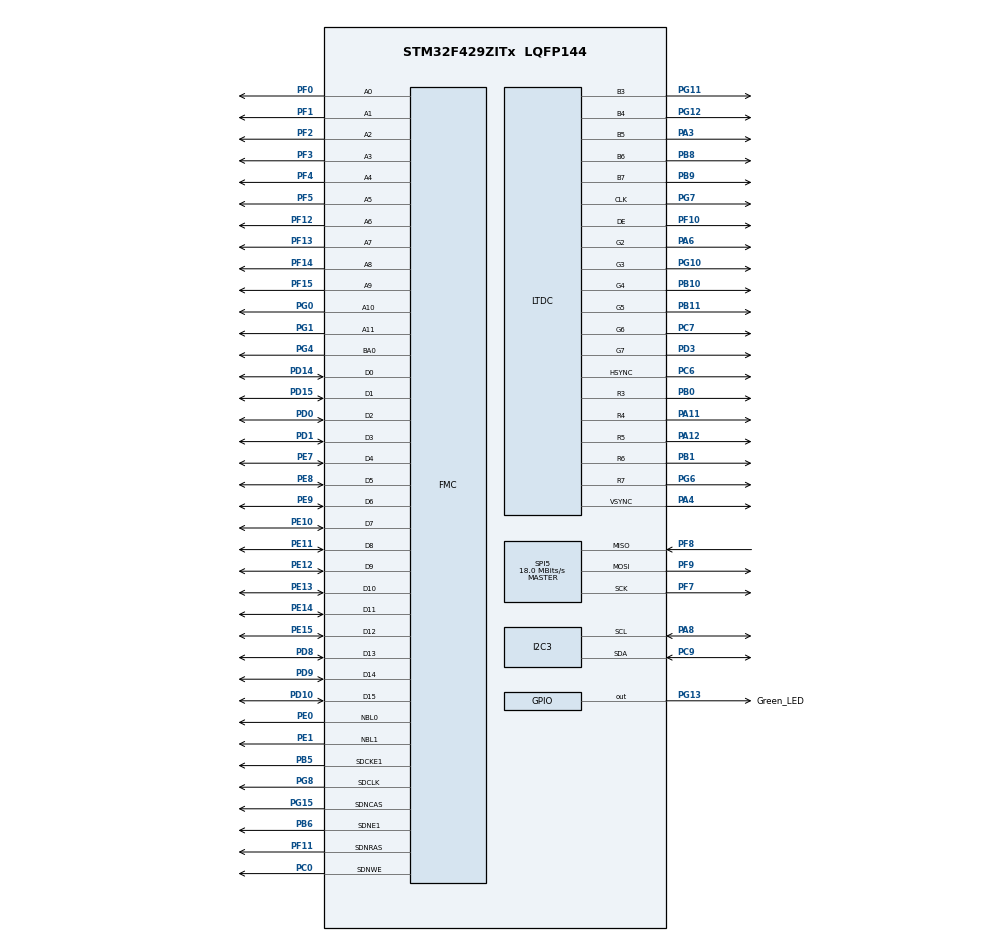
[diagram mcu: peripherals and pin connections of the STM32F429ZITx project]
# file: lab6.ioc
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Mcu.Family=STM32F4
Mcu.Name=STM32F429ZITx
Mcu.Package=LQFP144
NVIC.PriorityGroup=NVIC_PRIORITYGROUP_4
PA11.Mode=RGB565
PA11.Signal=LTDC_R4
PA12.Mode=RGB565
PA12.Signal=LTDC_R5
PA3.Mode=RGB565
PA3.Signal=LTDC_B5
PA4.Mode=RGB565
PA4.Signal=LTDC_VSYNC
PA6.Mode=RGB565
PA6.Signal=LTDC_G2
PA8.GPIO_Pu=GPIO_PULLUP
PA8.GPIO_Speed=GPIO_SPEED_FREQ_LOW
PA8.Mode=I2C
PA8.Signal=I2C3_SCL
PB0.Mode=RGB565
PB0.Signal=LTDC_R3
PB1.Mode=RGB565
PB1.Signal=LTDC_R6
PB10.Mode=RGB565
PB10.Signal=LTDC_G4
PB11.Mode=RGB565
PB11.Signal=LTDC_G5
PB5.Mode=SdramChipSelect2_2
PB5.Signal=FMC_SDCKE1
PB6.Mode=SdramChipSelect2_2
PB6.Signal=FMC_SDNE1
PB8.Mode=RGB565
PB8.Signal=LTDC_B6
PB9.Mode=RGB565
PB9.Signal=LTDC_B7
PC0.Signal=FMC_SDNWE
PC6.Mode=RGB565
PC6.Signal=LTDC_HSYNC
PC7.Mode=RGB565
PC7.Signal=LTDC_G6
PC9.GPIO_Pu=GPIO_PULLUP
PC9.GPIO_Speed=GPIO_SPEED_FREQ_LOW
PC9.Mode=I2C
PC9.Signal=I2C3_SDA
PD0.Signal=FMC_D2_DA2
PD1.Signal=FMC_D3_DA3
PD10.Signal=FMC_D15_DA15
PD14.Signal=FMC_D0_DA0
PD15.Signal=FMC_D1_DA1
PD3.Mode=RGB565
PD3.Signal=LTDC_G7
PD8.Signal=FMC_D13_DA13
PD9.Signal=FMC_D14_DA14
PE0.Signal=FMC_NBL0
PE1.Signal=FMC_NBL1
PE10.Signal=FMC_D7_DA7
PE11.Signal=FMC_D8_DA8
PE12.Signal=FMC_D9_DA9
PE13.Signal=FMC_D10_DA10
PE14.Signal=FMC_D11_DA11
PE15.Signal=FMC_D12_DA12
PE7.Signal=FMC_D4_DA4
PE8.Signal=FMC_D5_DA5
PE9.Signal=FMC_D6_DA6
PF0.Signal=FMC_A0
PF1.Signal=FMC_A1
PF10.Mode=RGB565
PF10.Signal=LTDC_DE
PF11.Signal=FMC_SDNRAS
PF12.Signal=FMC_A6
PF13.Signal=FMC_A7
PF14.Signal=FMC_A8
PF15.Signal=FMC_A9
PF2.Signal=FMC_A2
PF3.Signal=FMC_A3
PF4.Signal=FMC_A4
PF5.Signal=FMC_A5
PF7.Mode=Full_Duplex_Master
PF7.Signal=SPI5_SCK
PF8.Mode=Full_Duplex_Master
PF8.Signal=SPI5_MISO
PF9.Mode=Full_Duplex_Master
PF9.Signal=SPI5_MOSI
PG0.Signal=FMC_A10
PG1.Signal=FMC_A11
PG10.Mode=RGB565
PG10.Signal=LTDC_G3
PG11.Mode=RGB565
PG11.Signal=LTDC_B3
PG12.Mode=RGB565
PG12.Signal=LTDC_B4
PG13.GPIO_Label=Green_LED
PG13.GPIO_PuPd=GPIO_NOPULL
PG13.Signal=GPIO_Output
PG15.Signal=FMC_SDNCAS
PG4.Signal=FMC_A14_BA0
PG6.Mode=RGB565
PG6.Signal=LTDC_R7
PG7.Mode=RGB565
PG7.Signal=LTDC_CLK
PG8.Signal=FMC_SDCLK
ProjectManager.HeapSize=0x200
ProjectManager.StackSize=0x400
ProjectManager.TargetToolchain=STM32CubeIDE
RCC.48MHZClocksFreq_Value=48000000
RCC.AHBFreq_Value=72000000
RCC.APB1CLKDivider=RCC_HCLK_DIV2
RCC.APB1Freq_Value=36000000
RCC.APB1TimFreq_Value=72000000
RCC.APB2CLKDivider=RCC_HCLK_DIV2
RCC.APB2Freq_Value=36000000
RCC.APB2TimFreq_Value=72000000
RCC.CortexFreq_Value=72000000
RCC.HCLKFreq_Value=72000000
RCC.HSE_VALUE=8000000
RCC.HSI_VALUE=16000000
RCC.LSE_VALUE=32768
RCC.PLLN=72
RCC.PLLQ=3
RCC.PLLSAIDivR=RCC_PLLSAIDIVR_8
RCC.PLLSAIR=2
RCC.SYSCLKFreq_VALUE=72000000
RCC.SYSCLKSource=RCC_SYSCLKSOURCE_PLLCLK
RCC.VCOOutputFreq_Value=144000000
SH.FMC_A0.0=FMC_A0,12b-sda2
SH.FMC_A1.0=FMC_A1,12b-sda2
SH.FMC_A10.0=FMC_A10,12b-sda2
SH.FMC_A11.0=FMC_A11,12b-sda2
SH.FMC_A14_BA0.0=FMC_BA0,TwoSdramBanks2
SH.FMC_A2.0=FMC_A2,12b-sda2
SH.FMC_A3.0=FMC_A3,12b-sda2
SH.FMC_A4.0=FMC_A4,12b-sda2
SH.FMC_A5.0=FMC_A5,12b-sda2
SH.FMC_A6.0=FMC_A6,12b-sda2
SH.FMC_A7.0=FMC_A7,12b-sda2
SH.FMC_A8.0=FMC_A8,12b-sda2
SH.FMC_A9.0=FMC_A9,12b-sda2
SH.FMC_D0_DA0.0=FMC_D0,sd-16b-d2
SH.FMC_D10_DA10.0=FMC_D10,sd-16b-d2
SH.FMC_D11_DA11.0=FMC_D11,sd-16b-d2
SH.FMC_D12_DA12.0=FMC_D12,sd-16b-d2
SH.FMC_D13_DA13.0=FMC_D13,sd-16b-d2
SH.FMC_D14_DA14.0=FMC_D14,sd-16b-d2
SH.FMC_D15_DA15.0=FMC_D15,sd-16b-d2
SH.FMC_D1_DA1.0=FMC_D1,sd-16b-d2
SH.FMC_D2_DA2.0=FMC_D2,sd-16b-d2
SH.FMC_D3_DA3.0=FMC_D3,sd-16b-d2
SH.FMC_D4_DA4.0=FMC_D4,sd-16b-d2
SH.FMC_D5_DA5.0=FMC_D5,sd-16b-d2
SH.FMC_D6_DA6.0=FMC_D6,sd-16b-d2
SH.FMC_D7_DA7.0=FMC_D7,sd-16b-d2
SH.FMC_D8_DA8.0=FMC_D8,sd-16b-d2
SH.FMC_D9_DA9.0=FMC_D9,sd-16b-d2
SH.FMC_NBL0.0=FMC_NBL0,Sd2ByteEnable2
SH.FMC_NBL1.0=FMC_NBL1,Sd2ByteEnable2
SH.FMC_SDCLK.0=FMC_SDCLK,12b-sda2
SH.FMC_SDNCAS.0=FMC_SDNCAS,12b-sda2
SH.FMC_SDNRAS.0=FMC_SDNRAS,12b-sda2
SH.FMC_SDNWE.0=FMC_SDNWE,12b-sda2
SPI5.CalculateBaudRate=18.0 MBits/s
SPI5.Direction=SPI_DIRECTION_2LINES
SPI5.Mode=SPI_MODE_MASTER
SPI5.VirtualType=VM_MASTER
VP_DMA2D_VS_DMA2D.Mode=DMA2D_Activate
board=STM32F429I-DISC1

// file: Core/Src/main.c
/* USER CODE BEGIN Header */
/**
  ******************************************************************************
  * @file           : main.c
  * @brief          : Main program body
  ******************************************************************************
  * @attention
  *
  * Copyright (c) 2026 STMicroelectronics.
  * All rights reserved.
  *
  * This software is licensed under terms that can be found in the LICENSE file
  * in the root directory of this software component.
  * If no LICENSE file comes with this software, it is provided AS-IS.
  *
  ******************************************************************************
  */
/* USER CODE END Header */
#include "main.h"

/* USER CODE BEGIN Includes */
#include "stm32f429i_discovery.h"      // Pagrindinė plokštės biblioteka (LED, mygtukai)
#include "stm32f429i_discovery_lcd.h"  // Ekrano biblioteka
#include "stm32f429i_discovery_sdram.h"// Būtina ekrano atminties valdymui
#include <stdio.h>
/* USER CODE END Includes */

DMA2D_HandleTypeDef hdma2d;

I2C_HandleTypeDef hi2c3;

LTDC_HandleTypeDef hltdc;

SPI_HandleTypeDef hspi5;

SDRAM_HandleTypeDef hsdram2;

/* USER CODE BEGIN PV */
#define SLAVE_ADDR (0x3C << 1)
#define LCD_FB_START_ADDRESS 0xD0000000  // SDRAM pradžios adresas (BŪTINA PRIDĖTI)

uint8_t data_single = 0x2A;
uint8_t data_array[3] = {0x11, 0x22, 0x33};
char lcd_buffer[50];
/* USER CODE END PV */

void SystemClock_Config(void);
static void MX_GPIO_Init(void);
static void MX_I2C3_Init(void);
static void MX_DMA2D_Init(void);
static void MX_FMC_Init(void);
static void MX_LTDC_Init(void);
static void MX_SPI5_Init(void);

int main(void)
{

  /* MCU Configuration--------------------------------------------------------*/

  /* Reset of all peripherals, Initializes the Flash interface and the Systick. */
  HAL_Init();

  /* Configure the system clock */
  SystemClock_Config();

  /* Initialize all configured peripherals */
  MX_GPIO_Init();
  MX_I2C3_Init();
  MX_DMA2D_Init();
  MX_FMC_Init();
  MX_LTDC_Init();
  MX_SPI5_Init();
  /* USER CODE BEGIN 2 */
  BSP_SDRAM_Init();

  // 2. Inicializuojame LCD
  BSP_LCD_Init();

  // 3. Pasiruošiame sluoksnį (Layer) ir įjungiam vaizdą
  BSP_LCD_LayerDefaultInit(LCD_BACKGROUND_LAYER, LCD_FB_START_ADDRESS);
  BSP_LCD_SelectLayer(LCD_BACKGROUND_LAYER);
  BSP_LCD_DisplayOn();

  // 4. Nuvalome ekraną ir nustatome spalvas/šriftą
  BSP_LCD_Clear(LCD_COLOR_WHITE);
  BSP_LCD_SetTextColor(LCD_COLOR_BLUE);
  BSP_LCD_SetBackColor(LCD_COLOR_WHITE);
  BSP_LCD_SetFont(&Font16);

  // Testinis užrašas
  BSP_LCD_DisplayStringAtLine(0, (uint8_t*)"I2C Master Test");
  /* USER CODE END 2 */

  /* Infinite loop */
  /* USER CODE BEGIN WHILE */
  while (1)
    {
        // --- 1. Indikacija: Įjungiam LED (PG13) ---
        HAL_GPIO_WritePin(GPIOG, GPIO_PIN_13, GPIO_PIN_SET);

        // --- 2. PRIVALOMA DALIS: Siunčiame 1 baitą (0x2A) ---
        if (HAL_I2C_Master_Transmit(&hi2c3, SLAVE_ADDR, &data_single, 1, 100) == HAL_OK)
        {
            sprintf(lcd_buffer, "Sent Byte: 0x%02X ", data_single);
            BSP_LCD_DisplayStringAtLine(4, (uint8_t*)lcd_buffer);
        }
        else
        {
            BSP_LCD_DisplayStringAtLine(4, (uint8_t*)"Byte Send: ERROR    ");
        }

        HAL_Delay(100); // Maža pauzė tarp siuntimų

        // --- 3. PAPILDOMA DALIS: Siunčiame 3 baitus {0x11, 0x22, 0x33} ---
        if (HAL_I2C_Master_Transmit(&hi2c3, SLAVE_ADDR, data_array, 3, 100) == HAL_OK)
        {
            sprintf(lcd_buffer, "Sent Seq: %02X %02X %02X", data_array[0], data_array[1], data_array[2]);
            BSP_LCD_DisplayStringAtLine(6, (uint8_t*)lcd_buffer);
        }
        else
        {
            BSP_LCD_DisplayStringAtLine(6, (uint8_t*)"Seq Send: ERROR ");
        }

        // --- 4. Indikacija: Išjungiam LED po siuntimo ---
        HAL_GPIO_WritePin(GPIOG, GPIO_PIN_13, GPIO_PIN_RESET);

        // --- 5. Periodas: Laukiame 1 sekundę ---
        HAL_Delay(1000);

    /* USER CODE END WHILE */

    /* USER CODE BEGIN 3 */
    } // <--- Šitas uždaro WHILE ciklą
  /* USER CODE END 3 */
}

void SystemClock_Config(void)
{
  RCC_OscInitTypeDef RCC_OscInitStruct = {0};
  RCC_ClkInitTypeDef RCC_ClkInitStruct = {0};

  /** Configure the main internal regulator output voltage
  */
  __HAL_RCC_PWR_CLK_ENABLE();
  __HAL_PWR_VOLTAGESCALING_CONFIG(PWR_REGULATOR_VOLTAGE_SCALE3);

  /** Initializes the RCC Oscillators according to the specified parameters
  * in the RCC_OscInitTypeDef structure.
  */
  RCC_OscInitStruct.OscillatorType = RCC_OSCILLATORTYPE_HSI;
  RCC_OscInitStruct.HSIState = RCC_HSI_ON;
  RCC_OscInitStruct.HSICalibrationValue = RCC_HSICALIBRATION_DEFAULT;
  RCC_OscInitStruct.PLL.PLLState = RCC_PLL_ON;
  RCC_OscInitStruct.PLL.PLLSource = RCC_PLLSOURCE_HSI;
  RCC_OscInitStruct.PLL.PLLM = 16;
  RCC_OscInitStruct.PLL.PLLN = 72;
  RCC_OscInitStruct.PLL.PLLP = RCC_PLLP_DIV2;
  RCC_OscInitStruct.PLL.PLLQ = 3;
  if (HAL_RCC_OscConfig(&RCC_OscInitStruct) != HAL_OK)
  {
    Error_Handler();
  }

  /** Initializes the CPU, AHB and APB buses clocks
  */
  RCC_ClkInitStruct.ClockType = RCC_CLOCKTYPE_HCLK|RCC_CLOCKTYPE_SYSCLK
                              |RCC_CLOCKTYPE_PCLK1|RCC_CLOCKTYPE_PCLK2;
  RCC_ClkInitStruct.SYSCLKSource = RCC_SYSCLKSOURCE_PLLCLK;
  RCC_ClkInitStruct.AHBCLKDivider = RCC_SYSCLK_DIV1;
  RCC_ClkInitStruct.APB1CLKDivider = RCC_HCLK_DIV2;
  RCC_ClkInitStruct.APB2CLKDivider = RCC_HCLK_DIV2;

  if (HAL_RCC_ClockConfig(&RCC_ClkInitStruct, FLASH_LATENCY_2) != HAL_OK)
  {
    Error_Handler();
  }
}

static void MX_DMA2D_Init(void)
{

  hdma2d.Instance = DMA2D;
  hdma2d.Init.Mode = DMA2D_M2M;
  hdma2d.Init.ColorMode = DMA2D_OUTPUT_ARGB8888;
  hdma2d.Init.OutputOffset = 0;
  hdma2d.LayerCfg[1].InputOffset = 0;
  hdma2d.LayerCfg[1].InputColorMode = DMA2D_INPUT_ARGB8888;
  hdma2d.LayerCfg[1].AlphaMode = DMA2D_NO_MODIF_ALPHA;
  hdma2d.LayerCfg[1].InputAlpha = 0;
  if (HAL_DMA2D_Init(&hdma2d) != HAL_OK)
  {
    Error_Handler();
  }
  if (HAL_DMA2D_ConfigLayer(&hdma2d, 1) != HAL_OK)
  {
    Error_Handler();
  }

}

static void MX_I2C3_Init(void)
{

  hi2c3.Instance = I2C3;
  hi2c3.Init.ClockSpeed = 100000;
  hi2c3.Init.DutyCycle = I2C_DUTYCYCLE_2;
  hi2c3.Init.OwnAddress1 = 0;
  hi2c3.Init.AddressingMode = I2C_ADDRESSINGMODE_7BIT;
  hi2c3.Init.DualAddressMode = I2C_DUALADDRESS_DISABLE;
  hi2c3.Init.OwnAddress2 = 0;
  hi2c3.Init.GeneralCallMode = I2C_GENERALCALL_DISABLE;
  hi2c3.Init.NoStretchMode = I2C_NOSTRETCH_DISABLE;
  if (HAL_I2C_Init(&hi2c3) != HAL_OK)
  {
    Error_Handler();
  }

  /** Configure Analogue filter
  */
  if (HAL_I2CEx_ConfigAnalogFilter(&hi2c3, I2C_ANALOGFILTER_ENABLE) != HAL_OK)
  {
    Error_Handler();
  }

  /** Configure Digital filter
  */
  if (HAL_I2CEx_ConfigDigitalFilter(&hi2c3, 0) != HAL_OK)
  {
    Error_Handler();
  }

}

static void MX_LTDC_Init(void)
{

  LTDC_LayerCfgTypeDef pLayerCfg = {0};
  LTDC_LayerCfgTypeDef pLayerCfg1 = {0};

  hltdc.Instance = LTDC;
  hltdc.Init.HSPolarity = LTDC_HSPOLARITY_AL;
  hltdc.Init.VSPolarity = LTDC_VSPOLARITY_AL;
  hltdc.Init.DEPolarity = LTDC_DEPOLARITY_AL;
  hltdc.Init.PCPolarity = LTDC_PCPOLARITY_IPC;
  hltdc.Init.HorizontalSync = 7;
  hltdc.Init.VerticalSync = 3;
  hltdc.Init.AccumulatedHBP = 14;
  hltdc.Init.AccumulatedVBP = 5;
  hltdc.Init.AccumulatedActiveW = 654;
  hltdc.Init.AccumulatedActiveH = 485;
  hltdc.Init.TotalWidth = 660;
  hltdc.Init.TotalHeigh = 487;
  hltdc.Init.Backcolor.Blue = 0;
  hltdc.Init.Backcolor.Green = 0;
  hltdc.Init.Backcolor.Red = 0;
  if (HAL_LTDC_Init(&hltdc) != HAL_OK)
  {
    Error_Handler();
  }
  pLayerCfg.WindowX0 = 0;
  pLayerCfg.WindowX1 = 0;
  pLayerCfg.WindowY0 = 0;
  pLayerCfg.WindowY1 = 0;
  pLayerCfg.PixelFormat = LTDC_PIXEL_FORMAT_ARGB8888;
  pLayerCfg.Alpha = 0;
  pLayerCfg.Alpha0 = 0;
  pLayerCfg.BlendingFactor1 = LTDC_BLENDING_FACTOR1_CA;
  pLayerCfg.BlendingFactor2 = LTDC_BLENDING_FACTOR2_CA;
  pLayerCfg.FBStartAdress = 0;
  pLayerCfg.ImageWidth = 0;
  pLayerCfg.ImageHeight = 0;
  pLayerCfg.Backcolor.Blue = 0;
  pLayerCfg.Backcolor.Green = 0;
  pLayerCfg.Backcolor.Red = 0;
  if (HAL_LTDC_ConfigLayer(&hltdc, &pLayerCfg, 0) != HAL_OK)
  {
    Error_Handler();
  }
  pLayerCfg1.WindowX0 = 0;
  pLayerCfg1.WindowX1 = 0;
  pLayerCfg1.WindowY0 = 0;
  pLayerCfg1.WindowY1 = 0;
  pLayerCfg1.PixelFormat = LTDC_PIXEL_FORMAT_ARGB8888;
  pLayerCfg1.Alpha = 0;
  pLayerCfg1.Alpha0 = 0;
  pLayerCfg1.BlendingFactor1 = LTDC_BLENDING_FACTOR1_CA;
  pLayerCfg1.BlendingFactor2 = LTDC_BLENDING_FACTOR2_CA;
  pLayerCfg1.FBStartAdress = 0;
  pLayerCfg1.ImageWidth = 0;
  pLayerCfg1.ImageHeight = 0;
  pLayerCfg1.Backcolor.Blue = 0;
  pLayerCfg1.Backcolor.Green = 0;
  pLayerCfg1.Backcolor.Red = 0;
  if (HAL_LTDC_ConfigLayer(&hltdc, &pLayerCfg1, 1) != HAL_OK)
  {
    Error_Handler();
  }

}

static void MX_SPI5_Init(void)
{

  /* SPI5 parameter configuration*/
  hspi5.Instance = SPI5;
  hspi5.Init.Mode = SPI_MODE_MASTER;
  hspi5.Init.Direction = SPI_DIRECTION_2LINES;
  hspi5.Init.DataSize = SPI_DATASIZE_8BIT;
  hspi5.Init.CLKPolarity = SPI_POLARITY_LOW;
  hspi5.Init.CLKPhase = SPI_PHASE_1EDGE;
  hspi5.Init.NSS = SPI_NSS_SOFT;
  hspi5.Init.BaudRatePrescaler = SPI_BAUDRATEPRESCALER_2;
  hspi5.Init.FirstBit = SPI_FIRSTBIT_MSB;
  hspi5.Init.TIMode = SPI_TIMODE_DISABLE;
  hspi5.Init.CRCCalculation = SPI_CRCCALCULATION_DISABLE;
  hspi5.Init.CRCPolynomial = 10;
  if (HAL_SPI_Init(&hspi5) != HAL_OK)
  {
    Error_Handler();
  }

}

/* FMC initialization function */
static void MX_FMC_Init(void)
{

  FMC_SDRAM_TimingTypeDef SdramTiming = {0};

  /** Perform the SDRAM2 memory initialization sequence
  */
  hsdram2.Instance = FMC_SDRAM_DEVICE;
  /* hsdram2.Init */
  hsdram2.Init.SDBank = FMC_SDRAM_BANK2;
  hsdram2.Init.ColumnBitsNumber = FMC_SDRAM_COLUMN_BITS_NUM_8;
  hsdram2.Init.RowBitsNumber = FMC_SDRAM_ROW_BITS_NUM_12;
  hsdram2.Init.MemoryDataWidth = FMC_SDRAM_MEM_BUS_WIDTH_16;
  hsdram2.Init.InternalBankNumber = FMC_SDRAM_INTERN_BANKS_NUM_2;
  hsdram2.Init.CASLatency = FMC_SDRAM_CAS_LATENCY_1;
  hsdram2.Init.WriteProtection = FMC_SDRAM_WRITE_PROTECTION_DISABLE;
  hsdram2.Init.SDClockPeriod = FMC_SDRAM_CLOCK_DISABLE;
  hsdram2.Init.ReadBurst = FMC_SDRAM_RBURST_DISABLE;
  hsdram2.Init.ReadPipeDelay = FMC_SDRAM_RPIPE_DELAY_0;
  /* SdramTiming */
  SdramTiming.LoadToActiveDelay = 16;
  SdramTiming.ExitSelfRefreshDelay = 16;
  SdramTiming.SelfRefreshTime = 16;
  SdramTiming.RowCycleDelay = 16;
  SdramTiming.WriteRecoveryTime = 16;
  SdramTiming.RPDelay = 16;
  SdramTiming.RCDDelay = 16;

  if (HAL_SDRAM_Init(&hsdram2, &SdramTiming) != HAL_OK)
  {
    Error_Handler( );
  }

}

static void MX_GPIO_Init(void)
{
  GPIO_InitTypeDef GPIO_InitStruct = {0};

  /* GPIO Ports Clock Enable */
  __HAL_RCC_GPIOF_CLK_ENABLE();
  __HAL_RCC_GPIOC_CLK_ENABLE();
  __HAL_RCC_GPIOA_CLK_ENABLE();
  __HAL_RCC_GPIOB_CLK_ENABLE();
  __HAL_RCC_GPIOG_CLK_ENABLE();
  __HAL_RCC_GPIOE_CLK_ENABLE();
  __HAL_RCC_GPIOD_CLK_ENABLE();

  /*Configure GPIO pin Output Level */
  HAL_GPIO_WritePin(Green_LED_GPIO_Port, Green_LED_Pin, GPIO_PIN_RESET);

  /*Configure GPIO pin : Green_LED_Pin */
  GPIO_InitStruct.Pin = Green_LED_Pin;
  GPIO_InitStruct.Mode = GPIO_MODE_OUTPUT_PP;
  GPIO_InitStruct.Pull = GPIO_NOPULL;
  GPIO_InitStruct.Speed = GPIO_SPEED_FREQ_LOW;
  HAL_GPIO_Init(Green_LED_GPIO_Port, &GPIO_InitStruct);

}

void Error_Handler(void)
{
  __disable_irq();
  while (1)
  {
  }
}
